VERSION 5.7 ;
BUSBITCHARS "[]" ;
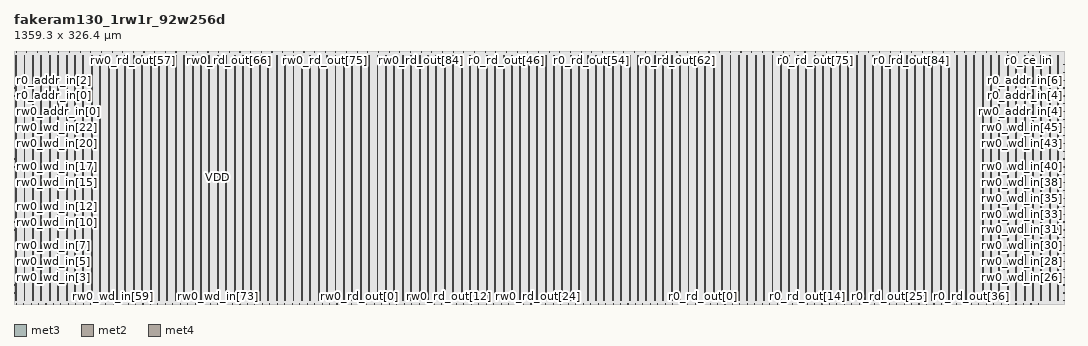
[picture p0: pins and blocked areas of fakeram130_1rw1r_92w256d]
MACRO fakeram130_1rw1r_92w256d
  FOREIGN fakeram130_1rw1r_92w256d 0 0 ;
  SYMMETRY X Y R90 ;
  SIZE 1359.300 BY 326.400 ;
  CLASS BLOCK ;
  PIN rw0_wd_in[0]
    DIRECTION INPUT ;
    USE SIGNAL ;
    SHAPE ABUTMENT ;
    PORT
      LAYER met3 ;
      RECT 0.000 3.930 0.900 4.230 ;
    END
  END rw0_wd_in[0]
  PIN rw0_wd_in[1]
    DIRECTION INPUT ;
    USE SIGNAL ;
    SHAPE ABUTMENT ;
    PORT
      LAYER met3 ;
      RECT 0.000 14.130 0.900 14.430 ;
    END
  END rw0_wd_in[1]
  PIN rw0_wd_in[2]
    DIRECTION INPUT ;
    USE SIGNAL ;
    SHAPE ABUTMENT ;
    PORT
      LAYER met3 ;
      RECT 0.000 24.330 0.900 24.630 ;
    END
  END rw0_wd_in[2]
  PIN rw0_wd_in[3]
    DIRECTION INPUT ;
    USE SIGNAL ;
    SHAPE ABUTMENT ;
    PORT
      LAYER met3 ;
      RECT 0.000 34.530 0.900 34.830 ;
    END
  END rw0_wd_in[3]
  PIN rw0_wd_in[4]
    DIRECTION INPUT ;
    USE SIGNAL ;
    SHAPE ABUTMENT ;
    PORT
      LAYER met3 ;
      RECT 0.000 44.730 0.900 45.030 ;
    END
  END rw0_wd_in[4]
  PIN rw0_wd_in[5]
    DIRECTION INPUT ;
    USE SIGNAL ;
    SHAPE ABUTMENT ;
    PORT
      LAYER met3 ;
      RECT 0.000 54.930 0.900 55.230 ;
    END
  END rw0_wd_in[5]
  PIN rw0_wd_in[6]
    DIRECTION INPUT ;
    USE SIGNAL ;
    SHAPE ABUTMENT ;
    PORT
      LAYER met3 ;
      RECT 0.000 65.130 0.900 65.430 ;
    END
  END rw0_wd_in[6]
  PIN rw0_wd_in[7]
    DIRECTION INPUT ;
    USE SIGNAL ;
    SHAPE ABUTMENT ;
    PORT
      LAYER met3 ;
      RECT 0.000 75.330 0.900 75.630 ;
    END
  END rw0_wd_in[7]
  PIN rw0_wd_in[8]
    DIRECTION INPUT ;
    USE SIGNAL ;
    SHAPE ABUTMENT ;
    PORT
      LAYER met3 ;
      RECT 0.000 85.530 0.900 85.830 ;
    END
  END rw0_wd_in[8]
  PIN rw0_wd_in[9]
    DIRECTION INPUT ;
    USE SIGNAL ;
    SHAPE ABUTMENT ;
    PORT
      LAYER met3 ;
      RECT 0.000 95.730 0.900 96.030 ;
    END
  END rw0_wd_in[9]
  PIN rw0_wd_in[10]
    DIRECTION INPUT ;
    USE SIGNAL ;
    SHAPE ABUTMENT ;
    PORT
      LAYER met3 ;
      RECT 0.000 105.930 0.900 106.230 ;
    END
  END rw0_wd_in[10]
  PIN rw0_wd_in[11]
    DIRECTION INPUT ;
    USE SIGNAL ;
    SHAPE ABUTMENT ;
    PORT
      LAYER met3 ;
      RECT 0.000 116.130 0.900 116.430 ;
    END
  END rw0_wd_in[11]
  PIN rw0_wd_in[12]
    DIRECTION INPUT ;
    USE SIGNAL ;
    SHAPE ABUTMENT ;
    PORT
      LAYER met3 ;
      RECT 0.000 126.330 0.900 126.630 ;
    END
  END rw0_wd_in[12]
  PIN rw0_wd_in[13]
    DIRECTION INPUT ;
    USE SIGNAL ;
    SHAPE ABUTMENT ;
    PORT
      LAYER met3 ;
      RECT 0.000 136.530 0.900 136.830 ;
    END
  END rw0_wd_in[13]
  PIN rw0_wd_in[14]
    DIRECTION INPUT ;
    USE SIGNAL ;
    SHAPE ABUTMENT ;
    PORT
      LAYER met3 ;
      RECT 0.000 146.730 0.900 147.030 ;
    END
  END rw0_wd_in[14]
  PIN rw0_wd_in[15]
    DIRECTION INPUT ;
    USE SIGNAL ;
    SHAPE ABUTMENT ;
    PORT
      LAYER met3 ;
      RECT 0.000 156.930 0.900 157.230 ;
    END
  END rw0_wd_in[15]
  PIN rw0_wd_in[16]
    DIRECTION INPUT ;
    USE SIGNAL ;
    SHAPE ABUTMENT ;
    PORT
      LAYER met3 ;
      RECT 0.000 167.130 0.900 167.430 ;
    END
  END rw0_wd_in[16]
  PIN rw0_wd_in[17]
    DIRECTION INPUT ;
    USE SIGNAL ;
    SHAPE ABUTMENT ;
    PORT
      LAYER met3 ;
      RECT 0.000 177.330 0.900 177.630 ;
    END
  END rw0_wd_in[17]
  PIN rw0_wd_in[18]
    DIRECTION INPUT ;
    USE SIGNAL ;
    SHAPE ABUTMENT ;
    PORT
      LAYER met3 ;
      RECT 0.000 187.530 0.900 187.830 ;
    END
  END rw0_wd_in[18]
  PIN rw0_wd_in[19]
    DIRECTION INPUT ;
    USE SIGNAL ;
    SHAPE ABUTMENT ;
    PORT
      LAYER met3 ;
      RECT 0.000 197.730 0.900 198.030 ;
    END
  END rw0_wd_in[19]
  PIN rw0_wd_in[20]
    DIRECTION INPUT ;
    USE SIGNAL ;
    SHAPE ABUTMENT ;
    PORT
      LAYER met3 ;
      RECT 0.000 207.930 0.900 208.230 ;
    END
  END rw0_wd_in[20]
  PIN rw0_wd_in[21]
    DIRECTION INPUT ;
    USE SIGNAL ;
    SHAPE ABUTMENT ;
    PORT
      LAYER met3 ;
      RECT 0.000 218.130 0.900 218.430 ;
    END
  END rw0_wd_in[21]
  PIN rw0_wd_in[22]
    DIRECTION INPUT ;
    USE SIGNAL ;
    SHAPE ABUTMENT ;
    PORT
      LAYER met3 ;
      RECT 0.000 228.330 0.900 228.630 ;
    END
  END rw0_wd_in[22]
  PIN rw0_wd_in[23]
    DIRECTION INPUT ;
    USE SIGNAL ;
    SHAPE ABUTMENT ;
    PORT
      LAYER met3 ;
      RECT 1358.400 3.930 1359.300 4.230 ;
    END
  END rw0_wd_in[23]
  PIN rw0_wd_in[24]
    DIRECTION INPUT ;
    USE SIGNAL ;
    SHAPE ABUTMENT ;
    PORT
      LAYER met3 ;
      RECT 1358.400 14.130 1359.300 14.430 ;
    END
  END rw0_wd_in[24]
  PIN rw0_wd_in[25]
    DIRECTION INPUT ;
    USE SIGNAL ;
    SHAPE ABUTMENT ;
    PORT
      LAYER met3 ;
      RECT 1358.400 24.330 1359.300 24.630 ;
    END
  END rw0_wd_in[25]
  PIN rw0_wd_in[26]
    DIRECTION INPUT ;
    USE SIGNAL ;
    SHAPE ABUTMENT ;
    PORT
      LAYER met3 ;
      RECT 1358.400 34.530 1359.300 34.830 ;
    END
  END rw0_wd_in[26]
  PIN rw0_wd_in[27]
    DIRECTION INPUT ;
    USE SIGNAL ;
    SHAPE ABUTMENT ;
    PORT
      LAYER met3 ;
      RECT 1358.400 44.730 1359.300 45.030 ;
    END
  END rw0_wd_in[27]
  PIN rw0_wd_in[28]
    DIRECTION INPUT ;
    USE SIGNAL ;
    SHAPE ABUTMENT ;
    PORT
      LAYER met3 ;
      RECT 1358.400 54.930 1359.300 55.230 ;
    END
  END rw0_wd_in[28]
  PIN rw0_wd_in[29]
    DIRECTION INPUT ;
    USE SIGNAL ;
    SHAPE ABUTMENT ;
    PORT
      LAYER met3 ;
      RECT 1358.400 65.130 1359.300 65.430 ;
    END
  END rw0_wd_in[29]
  PIN rw0_wd_in[30]
    DIRECTION INPUT ;
    USE SIGNAL ;
    SHAPE ABUTMENT ;
    PORT
      LAYER met3 ;
      RECT 1358.400 75.330 1359.300 75.630 ;
    END
  END rw0_wd_in[30]
  PIN rw0_wd_in[31]
    DIRECTION INPUT ;
    USE SIGNAL ;
    SHAPE ABUTMENT ;
    PORT
      LAYER met3 ;
      RECT 1358.400 85.530 1359.300 85.830 ;
    END
  END rw0_wd_in[31]
  PIN rw0_wd_in[32]
    DIRECTION INPUT ;
    USE SIGNAL ;
    SHAPE ABUTMENT ;
    PORT
      LAYER met3 ;
      RECT 1358.400 95.730 1359.300 96.030 ;
    END
  END rw0_wd_in[32]
  PIN rw0_wd_in[33]
    DIRECTION INPUT ;
    USE SIGNAL ;
    SHAPE ABUTMENT ;
    PORT
      LAYER met3 ;
      RECT 1358.400 105.930 1359.300 106.230 ;
    END
  END rw0_wd_in[33]
  PIN rw0_wd_in[34]
    DIRECTION INPUT ;
    USE SIGNAL ;
    SHAPE ABUTMENT ;
    PORT
      LAYER met3 ;
      RECT 1358.400 116.130 1359.300 116.430 ;
    END
  END rw0_wd_in[34]
  PIN rw0_wd_in[35]
    DIRECTION INPUT ;
    USE SIGNAL ;
    SHAPE ABUTMENT ;
    PORT
      LAYER met3 ;
      RECT 1358.400 126.330 1359.300 126.630 ;
    END
  END rw0_wd_in[35]
  PIN rw0_wd_in[36]
    DIRECTION INPUT ;
    USE SIGNAL ;
    SHAPE ABUTMENT ;
    PORT
      LAYER met3 ;
      RECT 1358.400 136.530 1359.300 136.830 ;
    END
  END rw0_wd_in[36]
  PIN rw0_wd_in[37]
    DIRECTION INPUT ;
    USE SIGNAL ;
    SHAPE ABUTMENT ;
    PORT
      LAYER met3 ;
      RECT 1358.400 146.730 1359.300 147.030 ;
    END
  END rw0_wd_in[37]
  PIN rw0_wd_in[38]
    DIRECTION INPUT ;
    USE SIGNAL ;
    SHAPE ABUTMENT ;
    PORT
      LAYER met3 ;
      RECT 1358.400 156.930 1359.300 157.230 ;
    END
  END rw0_wd_in[38]
  PIN rw0_wd_in[39]
    DIRECTION INPUT ;
    USE SIGNAL ;
    SHAPE ABUTMENT ;
    PORT
      LAYER met3 ;
      RECT 1358.400 167.130 1359.300 167.430 ;
    END
  END rw0_wd_in[39]
  PIN rw0_wd_in[40]
    DIRECTION INPUT ;
    USE SIGNAL ;
    SHAPE ABUTMENT ;
    PORT
      LAYER met3 ;
      RECT 1358.400 177.330 1359.300 177.630 ;
    END
  END rw0_wd_in[40]
  PIN rw0_wd_in[41]
    DIRECTION INPUT ;
    USE SIGNAL ;
    SHAPE ABUTMENT ;
    PORT
      LAYER met3 ;
      RECT 1358.400 187.530 1359.300 187.830 ;
    END
  END rw0_wd_in[41]
  PIN rw0_wd_in[42]
    DIRECTION INPUT ;
    USE SIGNAL ;
    SHAPE ABUTMENT ;
    PORT
      LAYER met3 ;
      RECT 1358.400 197.730 1359.300 198.030 ;
    END
  END rw0_wd_in[42]
  PIN rw0_wd_in[43]
    DIRECTION INPUT ;
    USE SIGNAL ;
    SHAPE ABUTMENT ;
    PORT
      LAYER met3 ;
      RECT 1358.400 207.930 1359.300 208.230 ;
    END
  END rw0_wd_in[43]
  PIN rw0_wd_in[44]
    DIRECTION INPUT ;
    USE SIGNAL ;
    SHAPE ABUTMENT ;
    PORT
      LAYER met3 ;
      RECT 1358.400 218.130 1359.300 218.430 ;
    END
  END rw0_wd_in[44]
  PIN rw0_wd_in[45]
    DIRECTION INPUT ;
    USE SIGNAL ;
    SHAPE ABUTMENT ;
    PORT
      LAYER met3 ;
      RECT 1358.400 228.330 1359.300 228.630 ;
    END
  END rw0_wd_in[45]
  PIN rw0_wd_in[46]
    DIRECTION OUTPUT ;
    USE SIGNAL ;
    SHAPE ABUTMENT ;
    PORT
      LAYER met2 ;
      RECT 2.690 0.000 2.830 0.420 ;
    END
  END rw0_wd_in[46]
  PIN rw0_wd_in[47]
    DIRECTION OUTPUT ;
    USE SIGNAL ;
    SHAPE ABUTMENT ;
    PORT
      LAYER met2 ;
      RECT 12.350 0.000 12.490 0.420 ;
    END
  END rw0_wd_in[47]
  PIN rw0_wd_in[48]
    DIRECTION OUTPUT ;
    USE SIGNAL ;
    SHAPE ABUTMENT ;
    PORT
      LAYER met2 ;
      RECT 22.010 0.000 22.150 0.420 ;
    END
  END rw0_wd_in[48]
  PIN rw0_wd_in[49]
    DIRECTION OUTPUT ;
    USE SIGNAL ;
    SHAPE ABUTMENT ;
    PORT
      LAYER met2 ;
      RECT 31.670 0.000 31.810 0.420 ;
    END
  END rw0_wd_in[49]
  PIN rw0_wd_in[50]
    DIRECTION OUTPUT ;
    USE SIGNAL ;
    SHAPE ABUTMENT ;
    PORT
      LAYER met2 ;
      RECT 41.330 0.000 41.470 0.420 ;
    END
  END rw0_wd_in[50]
  PIN rw0_wd_in[51]
    DIRECTION OUTPUT ;
    USE SIGNAL ;
    SHAPE ABUTMENT ;
    PORT
      LAYER met2 ;
      RECT 50.990 0.000 51.130 0.420 ;
    END
  END rw0_wd_in[51]
  PIN rw0_wd_in[52]
    DIRECTION OUTPUT ;
    USE SIGNAL ;
    SHAPE ABUTMENT ;
    PORT
      LAYER met2 ;
      RECT 60.650 0.000 60.790 0.420 ;
    END
  END rw0_wd_in[52]
  PIN rw0_wd_in[53]
    DIRECTION OUTPUT ;
    USE SIGNAL ;
    SHAPE ABUTMENT ;
    PORT
      LAYER met2 ;
      RECT 70.310 0.000 70.450 0.420 ;
    END
  END rw0_wd_in[53]
  PIN rw0_wd_in[54]
    DIRECTION OUTPUT ;
    USE SIGNAL ;
    SHAPE ABUTMENT ;
    PORT
      LAYER met2 ;
      RECT 79.970 0.000 80.110 0.420 ;
    END
  END rw0_wd_in[54]
  PIN rw0_wd_in[55]
    DIRECTION OUTPUT ;
    USE SIGNAL ;
    SHAPE ABUTMENT ;
    PORT
      LAYER met2 ;
      RECT 89.630 0.000 89.770 0.420 ;
    END
  END rw0_wd_in[55]
  PIN rw0_wd_in[56]
    DIRECTION OUTPUT ;
    USE SIGNAL ;
    SHAPE ABUTMENT ;
    PORT
      LAYER met2 ;
      RECT 99.290 0.000 99.430 0.420 ;
    END
  END rw0_wd_in[56]
  PIN rw0_wd_in[57]
    DIRECTION OUTPUT ;
    USE SIGNAL ;
    SHAPE ABUTMENT ;
    PORT
      LAYER met2 ;
      RECT 108.950 0.000 109.090 0.420 ;
    END
  END rw0_wd_in[57]
  PIN rw0_wd_in[58]
    DIRECTION OUTPUT ;
    USE SIGNAL ;
    SHAPE ABUTMENT ;
    PORT
      LAYER met2 ;
      RECT 118.610 0.000 118.750 0.420 ;
    END
  END rw0_wd_in[58]
  PIN rw0_wd_in[59]
    DIRECTION OUTPUT ;
    USE SIGNAL ;
    SHAPE ABUTMENT ;
    PORT
      LAYER met2 ;
      RECT 128.270 0.000 128.410 0.420 ;
    END
  END rw0_wd_in[59]
  PIN rw0_wd_in[60]
    DIRECTION OUTPUT ;
    USE SIGNAL ;
    SHAPE ABUTMENT ;
    PORT
      LAYER met2 ;
      RECT 137.930 0.000 138.070 0.420 ;
    END
  END rw0_wd_in[60]
  PIN rw0_wd_in[61]
    DIRECTION OUTPUT ;
    USE SIGNAL ;
    SHAPE ABUTMENT ;
    PORT
      LAYER met2 ;
      RECT 147.590 0.000 147.730 0.420 ;
    END
  END rw0_wd_in[61]
  PIN rw0_wd_in[62]
    DIRECTION OUTPUT ;
    USE SIGNAL ;
    SHAPE ABUTMENT ;
    PORT
      LAYER met2 ;
      RECT 157.250 0.000 157.390 0.420 ;
    END
  END rw0_wd_in[62]
  PIN rw0_wd_in[63]
    DIRECTION OUTPUT ;
    USE SIGNAL ;
    SHAPE ABUTMENT ;
    PORT
      LAYER met2 ;
      RECT 166.910 0.000 167.050 0.420 ;
    END
  END rw0_wd_in[63]
  PIN rw0_wd_in[64]
    DIRECTION OUTPUT ;
    USE SIGNAL ;
    SHAPE ABUTMENT ;
    PORT
      LAYER met2 ;
      RECT 176.570 0.000 176.710 0.420 ;
    END
  END rw0_wd_in[64]
  PIN rw0_wd_in[65]
    DIRECTION OUTPUT ;
    USE SIGNAL ;
    SHAPE ABUTMENT ;
    PORT
      LAYER met2 ;
      RECT 186.230 0.000 186.370 0.420 ;
    END
  END rw0_wd_in[65]
  PIN rw0_wd_in[66]
    DIRECTION OUTPUT ;
    USE SIGNAL ;
    SHAPE ABUTMENT ;
    PORT
      LAYER met2 ;
      RECT 195.890 0.000 196.030 0.420 ;
    END
  END rw0_wd_in[66]
  PIN rw0_wd_in[67]
    DIRECTION OUTPUT ;
    USE SIGNAL ;
    SHAPE ABUTMENT ;
    PORT
      LAYER met2 ;
      RECT 205.550 0.000 205.690 0.420 ;
    END
  END rw0_wd_in[67]
  PIN rw0_wd_in[68]
    DIRECTION OUTPUT ;
    USE SIGNAL ;
    SHAPE ABUTMENT ;
    PORT
      LAYER met2 ;
      RECT 215.210 0.000 215.350 0.420 ;
    END
  END rw0_wd_in[68]
  PIN rw0_wd_in[69]
    DIRECTION OUTPUT ;
    USE SIGNAL ;
    SHAPE ABUTMENT ;
    PORT
      LAYER met2 ;
      RECT 224.870 0.000 225.010 0.420 ;
    END
  END rw0_wd_in[69]
  PIN rw0_wd_in[70]
    DIRECTION OUTPUT ;
    USE SIGNAL ;
    SHAPE ABUTMENT ;
    PORT
      LAYER met2 ;
      RECT 234.530 0.000 234.670 0.420 ;
    END
  END rw0_wd_in[70]
  PIN rw0_wd_in[71]
    DIRECTION OUTPUT ;
    USE SIGNAL ;
    SHAPE ABUTMENT ;
    PORT
      LAYER met2 ;
      RECT 244.190 0.000 244.330 0.420 ;
    END
  END rw0_wd_in[71]
  PIN rw0_wd_in[72]
    DIRECTION OUTPUT ;
    USE SIGNAL ;
    SHAPE ABUTMENT ;
    PORT
      LAYER met2 ;
      RECT 253.850 0.000 253.990 0.420 ;
    END
  END rw0_wd_in[72]
  PIN rw0_wd_in[73]
    DIRECTION OUTPUT ;
    USE SIGNAL ;
    SHAPE ABUTMENT ;
    PORT
      LAYER met2 ;
      RECT 263.510 0.000 263.650 0.420 ;
    END
  END rw0_wd_in[73]
  PIN rw0_wd_in[74]
    DIRECTION OUTPUT ;
    USE SIGNAL ;
    SHAPE ABUTMENT ;
    PORT
      LAYER met2 ;
      RECT 273.170 0.000 273.310 0.420 ;
    END
  END rw0_wd_in[74]
  PIN rw0_wd_in[75]
    DIRECTION OUTPUT ;
    USE SIGNAL ;
    SHAPE ABUTMENT ;
    PORT
      LAYER met2 ;
      RECT 282.830 0.000 282.970 0.420 ;
    END
  END rw0_wd_in[75]
  PIN rw0_wd_in[76]
    DIRECTION OUTPUT ;
    USE SIGNAL ;
    SHAPE ABUTMENT ;
    PORT
      LAYER met2 ;
      RECT 292.490 0.000 292.630 0.420 ;
    END
  END rw0_wd_in[76]
  PIN rw0_wd_in[77]
    DIRECTION OUTPUT ;
    USE SIGNAL ;
    SHAPE ABUTMENT ;
    PORT
      LAYER met2 ;
      RECT 302.150 0.000 302.290 0.420 ;
    END
  END rw0_wd_in[77]
  PIN rw0_wd_in[78]
    DIRECTION OUTPUT ;
    USE SIGNAL ;
    SHAPE ABUTMENT ;
    PORT
      LAYER met2 ;
      RECT 311.810 0.000 311.950 0.420 ;
    END
  END rw0_wd_in[78]
  PIN rw0_wd_in[79]
    DIRECTION OUTPUT ;
    USE SIGNAL ;
    SHAPE ABUTMENT ;
    PORT
      LAYER met2 ;
      RECT 321.470 0.000 321.610 0.420 ;
    END
  END rw0_wd_in[79]
  PIN rw0_wd_in[80]
    DIRECTION OUTPUT ;
    USE SIGNAL ;
    SHAPE ABUTMENT ;
    PORT
      LAYER met2 ;
      RECT 331.130 0.000 331.270 0.420 ;
    END
  END rw0_wd_in[80]
  PIN rw0_wd_in[81]
    DIRECTION OUTPUT ;
    USE SIGNAL ;
    SHAPE ABUTMENT ;
    PORT
      LAYER met2 ;
      RECT 340.790 0.000 340.930 0.420 ;
    END
  END rw0_wd_in[81]
  PIN rw0_wd_in[82]
    DIRECTION OUTPUT ;
    USE SIGNAL ;
    SHAPE ABUTMENT ;
    PORT
      LAYER met2 ;
      RECT 350.450 0.000 350.590 0.420 ;
    END
  END rw0_wd_in[82]
  PIN rw0_wd_in[83]
    DIRECTION OUTPUT ;
    USE SIGNAL ;
    SHAPE ABUTMENT ;
    PORT
      LAYER met2 ;
      RECT 360.110 0.000 360.250 0.420 ;
    END
  END rw0_wd_in[83]
  PIN rw0_wd_in[84]
    DIRECTION OUTPUT ;
    USE SIGNAL ;
    SHAPE ABUTMENT ;
    PORT
      LAYER met2 ;
      RECT 369.770 0.000 369.910 0.420 ;
    END
  END rw0_wd_in[84]
  PIN rw0_wd_in[85]
    DIRECTION OUTPUT ;
    USE SIGNAL ;
    SHAPE ABUTMENT ;
    PORT
      LAYER met2 ;
      RECT 379.430 0.000 379.570 0.420 ;
    END
  END rw0_wd_in[85]
  PIN rw0_wd_in[86]
    DIRECTION OUTPUT ;
    USE SIGNAL ;
    SHAPE ABUTMENT ;
    PORT
      LAYER met2 ;
      RECT 389.090 0.000 389.230 0.420 ;
    END
  END rw0_wd_in[86]
  PIN rw0_wd_in[87]
    DIRECTION OUTPUT ;
    USE SIGNAL ;
    SHAPE ABUTMENT ;
    PORT
      LAYER met2 ;
      RECT 398.750 0.000 398.890 0.420 ;
    END
  END rw0_wd_in[87]
  PIN rw0_wd_in[88]
    DIRECTION OUTPUT ;
    USE SIGNAL ;
    SHAPE ABUTMENT ;
    PORT
      LAYER met2 ;
      RECT 408.410 0.000 408.550 0.420 ;
    END
  END rw0_wd_in[88]
  PIN rw0_wd_in[89]
    DIRECTION OUTPUT ;
    USE SIGNAL ;
    SHAPE ABUTMENT ;
    PORT
      LAYER met2 ;
      RECT 418.070 0.000 418.210 0.420 ;
    END
  END rw0_wd_in[89]
  PIN rw0_wd_in[90]
    DIRECTION OUTPUT ;
    USE SIGNAL ;
    SHAPE ABUTMENT ;
    PORT
      LAYER met2 ;
      RECT 427.730 0.000 427.870 0.420 ;
    END
  END rw0_wd_in[90]
  PIN rw0_wd_in[91]
    DIRECTION OUTPUT ;
    USE SIGNAL ;
    SHAPE ABUTMENT ;
    PORT
      LAYER met2 ;
      RECT 437.390 0.000 437.530 0.420 ;
    END
  END rw0_wd_in[91]
  PIN rw0_rd_out[0]
    DIRECTION OUTPUT ;
    USE SIGNAL ;
    SHAPE ABUTMENT ;
    PORT
      LAYER met2 ;
      RECT 447.050 0.000 447.190 0.420 ;
    END
  END rw0_rd_out[0]
  PIN rw0_rd_out[1]
    DIRECTION OUTPUT ;
    USE SIGNAL ;
    SHAPE ABUTMENT ;
    PORT
      LAYER met2 ;
      RECT 456.710 0.000 456.850 0.420 ;
    END
  END rw0_rd_out[1]
  PIN rw0_rd_out[2]
    DIRECTION OUTPUT ;
    USE SIGNAL ;
    SHAPE ABUTMENT ;
    PORT
      LAYER met2 ;
      RECT 466.370 0.000 466.510 0.420 ;
    END
  END rw0_rd_out[2]
  PIN rw0_rd_out[3]
    DIRECTION OUTPUT ;
    USE SIGNAL ;
    SHAPE ABUTMENT ;
    PORT
      LAYER met2 ;
      RECT 476.030 0.000 476.170 0.420 ;
    END
  END rw0_rd_out[3]
  PIN rw0_rd_out[4]
    DIRECTION OUTPUT ;
    USE SIGNAL ;
    SHAPE ABUTMENT ;
    PORT
      LAYER met2 ;
      RECT 485.690 0.000 485.830 0.420 ;
    END
  END rw0_rd_out[4]
  PIN rw0_rd_out[5]
    DIRECTION OUTPUT ;
    USE SIGNAL ;
    SHAPE ABUTMENT ;
    PORT
      LAYER met2 ;
      RECT 495.350 0.000 495.490 0.420 ;
    END
  END rw0_rd_out[5]
  PIN rw0_rd_out[6]
    DIRECTION OUTPUT ;
    USE SIGNAL ;
    SHAPE ABUTMENT ;
    PORT
      LAYER met2 ;
      RECT 505.010 0.000 505.150 0.420 ;
    END
  END rw0_rd_out[6]
  PIN rw0_rd_out[7]
    DIRECTION OUTPUT ;
    USE SIGNAL ;
    SHAPE ABUTMENT ;
    PORT
      LAYER met2 ;
      RECT 514.670 0.000 514.810 0.420 ;
    END
  END rw0_rd_out[7]
  PIN rw0_rd_out[8]
    DIRECTION OUTPUT ;
    USE SIGNAL ;
    SHAPE ABUTMENT ;
    PORT
      LAYER met2 ;
      RECT 524.330 0.000 524.470 0.420 ;
    END
  END rw0_rd_out[8]
  PIN rw0_rd_out[9]
    DIRECTION OUTPUT ;
    USE SIGNAL ;
    SHAPE ABUTMENT ;
    PORT
      LAYER met2 ;
      RECT 533.990 0.000 534.130 0.420 ;
    END
  END rw0_rd_out[9]
  PIN rw0_rd_out[10]
    DIRECTION OUTPUT ;
    USE SIGNAL ;
    SHAPE ABUTMENT ;
    PORT
      LAYER met2 ;
      RECT 543.650 0.000 543.790 0.420 ;
    END
  END rw0_rd_out[10]
  PIN rw0_rd_out[11]
    DIRECTION OUTPUT ;
    USE SIGNAL ;
    SHAPE ABUTMENT ;
    PORT
      LAYER met2 ;
      RECT 553.310 0.000 553.450 0.420 ;
    END
  END rw0_rd_out[11]
  PIN rw0_rd_out[12]
    DIRECTION OUTPUT ;
    USE SIGNAL ;
    SHAPE ABUTMENT ;
    PORT
      LAYER met2 ;
      RECT 562.970 0.000 563.110 0.420 ;
    END
  END rw0_rd_out[12]
  PIN rw0_rd_out[13]
    DIRECTION OUTPUT ;
    USE SIGNAL ;
    SHAPE ABUTMENT ;
    PORT
      LAYER met2 ;
      RECT 572.630 0.000 572.770 0.420 ;
    END
  END rw0_rd_out[13]
  PIN rw0_rd_out[14]
    DIRECTION OUTPUT ;
    USE SIGNAL ;
    SHAPE ABUTMENT ;
    PORT
      LAYER met2 ;
      RECT 582.290 0.000 582.430 0.420 ;
    END
  END rw0_rd_out[14]
  PIN rw0_rd_out[15]
    DIRECTION OUTPUT ;
    USE SIGNAL ;
    SHAPE ABUTMENT ;
    PORT
      LAYER met2 ;
      RECT 591.950 0.000 592.090 0.420 ;
    END
  END rw0_rd_out[15]
  PIN rw0_rd_out[16]
    DIRECTION OUTPUT ;
    USE SIGNAL ;
    SHAPE ABUTMENT ;
    PORT
      LAYER met2 ;
      RECT 601.610 0.000 601.750 0.420 ;
    END
  END rw0_rd_out[16]
  PIN rw0_rd_out[17]
    DIRECTION OUTPUT ;
    USE SIGNAL ;
    SHAPE ABUTMENT ;
    PORT
      LAYER met2 ;
      RECT 611.270 0.000 611.410 0.420 ;
    END
  END rw0_rd_out[17]
  PIN rw0_rd_out[18]
    DIRECTION OUTPUT ;
    USE SIGNAL ;
    SHAPE ABUTMENT ;
    PORT
      LAYER met2 ;
      RECT 620.930 0.000 621.070 0.420 ;
    END
  END rw0_rd_out[18]
  PIN rw0_rd_out[19]
    DIRECTION OUTPUT ;
    USE SIGNAL ;
    SHAPE ABUTMENT ;
    PORT
      LAYER met2 ;
      RECT 630.590 0.000 630.730 0.420 ;
    END
  END rw0_rd_out[19]
  PIN rw0_rd_out[20]
    DIRECTION OUTPUT ;
    USE SIGNAL ;
    SHAPE ABUTMENT ;
    PORT
      LAYER met2 ;
      RECT 640.250 0.000 640.390 0.420 ;
    END
  END rw0_rd_out[20]
  PIN rw0_rd_out[21]
    DIRECTION OUTPUT ;
    USE SIGNAL ;
    SHAPE ABUTMENT ;
    PORT
      LAYER met2 ;
      RECT 649.910 0.000 650.050 0.420 ;
    END
  END rw0_rd_out[21]
  PIN rw0_rd_out[22]
    DIRECTION OUTPUT ;
    USE SIGNAL ;
    SHAPE ABUTMENT ;
    PORT
      LAYER met2 ;
      RECT 659.570 0.000 659.710 0.420 ;
    END
  END rw0_rd_out[22]
  PIN rw0_rd_out[23]
    DIRECTION OUTPUT ;
    USE SIGNAL ;
    SHAPE ABUTMENT ;
    PORT
      LAYER met2 ;
      RECT 669.230 0.000 669.370 0.420 ;
    END
  END rw0_rd_out[23]
  PIN rw0_rd_out[24]
    DIRECTION OUTPUT ;
    USE SIGNAL ;
    SHAPE ABUTMENT ;
    PORT
      LAYER met2 ;
      RECT 678.890 0.000 679.030 0.420 ;
    END
  END rw0_rd_out[24]
  PIN rw0_rd_out[25]
    DIRECTION OUTPUT ;
    USE SIGNAL ;
    SHAPE ABUTMENT ;
    PORT
      LAYER met2 ;
      RECT 688.550 0.000 688.690 0.420 ;
    END
  END rw0_rd_out[25]
  PIN rw0_rd_out[26]
    DIRECTION OUTPUT ;
    USE SIGNAL ;
    SHAPE ABUTMENT ;
    PORT
      LAYER met2 ;
      RECT 698.210 0.000 698.350 0.420 ;
    END
  END rw0_rd_out[26]
  PIN rw0_rd_out[27]
    DIRECTION OUTPUT ;
    USE SIGNAL ;
    SHAPE ABUTMENT ;
    PORT
      LAYER met2 ;
      RECT 707.870 0.000 708.010 0.420 ;
    END
  END rw0_rd_out[27]
  PIN rw0_rd_out[28]
    DIRECTION OUTPUT ;
    USE SIGNAL ;
    SHAPE ABUTMENT ;
    PORT
      LAYER met2 ;
      RECT 717.530 0.000 717.670 0.420 ;
    END
  END rw0_rd_out[28]
  PIN rw0_rd_out[29]
    DIRECTION OUTPUT ;
    USE SIGNAL ;
    SHAPE ABUTMENT ;
    PORT
      LAYER met2 ;
      RECT 727.190 0.000 727.330 0.420 ;
    END
  END rw0_rd_out[29]
  PIN rw0_rd_out[30]
    DIRECTION OUTPUT ;
    USE SIGNAL ;
    SHAPE ABUTMENT ;
    PORT
      LAYER met2 ;
      RECT 736.850 0.000 736.990 0.420 ;
    END
  END rw0_rd_out[30]
  PIN rw0_rd_out[31]
    DIRECTION OUTPUT ;
    USE SIGNAL ;
    SHAPE ABUTMENT ;
    PORT
      LAYER met2 ;
      RECT 746.510 0.000 746.650 0.420 ;
    END
  END rw0_rd_out[31]
  PIN rw0_rd_out[32]
    DIRECTION OUTPUT ;
    USE SIGNAL ;
    SHAPE ABUTMENT ;
    PORT
      LAYER met2 ;
      RECT 756.170 0.000 756.310 0.420 ;
    END
  END rw0_rd_out[32]
  PIN rw0_rd_out[33]
    DIRECTION OUTPUT ;
    USE SIGNAL ;
    SHAPE ABUTMENT ;
    PORT
      LAYER met2 ;
      RECT 765.830 0.000 765.970 0.420 ;
    END
  END rw0_rd_out[33]
  PIN rw0_rd_out[34]
    DIRECTION OUTPUT ;
    USE SIGNAL ;
    SHAPE ABUTMENT ;
    PORT
      LAYER met2 ;
      RECT 775.490 0.000 775.630 0.420 ;
    END
  END rw0_rd_out[34]
  PIN rw0_rd_out[35]
    DIRECTION OUTPUT ;
    USE SIGNAL ;
    SHAPE ABUTMENT ;
    PORT
      LAYER met2 ;
      RECT 785.150 0.000 785.290 0.420 ;
    END
  END rw0_rd_out[35]
  PIN rw0_rd_out[36]
    DIRECTION OUTPUT ;
    USE SIGNAL ;
    SHAPE ABUTMENT ;
    PORT
      LAYER met2 ;
      RECT 794.810 0.000 794.950 0.420 ;
    END
  END rw0_rd_out[36]
  PIN rw0_rd_out[37]
    DIRECTION OUTPUT ;
    USE SIGNAL ;
    SHAPE ABUTMENT ;
    PORT
      LAYER met2 ;
      RECT 804.470 0.000 804.610 0.420 ;
    END
  END rw0_rd_out[37]
  PIN rw0_rd_out[38]
    DIRECTION OUTPUT ;
    USE SIGNAL ;
    SHAPE ABUTMENT ;
    PORT
      LAYER met2 ;
      RECT 814.130 0.000 814.270 0.420 ;
    END
  END rw0_rd_out[38]
  PIN rw0_rd_out[39]
    DIRECTION OUTPUT ;
    USE SIGNAL ;
    SHAPE ABUTMENT ;
    PORT
      LAYER met2 ;
      RECT 823.790 0.000 823.930 0.420 ;
    END
  END rw0_rd_out[39]
  PIN rw0_rd_out[40]
    DIRECTION OUTPUT ;
    USE SIGNAL ;
    SHAPE ABUTMENT ;
    PORT
      LAYER met2 ;
      RECT 833.450 0.000 833.590 0.420 ;
    END
  END rw0_rd_out[40]
  PIN rw0_rd_out[41]
    DIRECTION OUTPUT ;
    USE SIGNAL ;
    SHAPE ABUTMENT ;
    PORT
      LAYER met2 ;
      RECT 843.110 0.000 843.250 0.420 ;
    END
  END rw0_rd_out[41]
  PIN rw0_rd_out[42]
    DIRECTION OUTPUT ;
    USE SIGNAL ;
    SHAPE ABUTMENT ;
    PORT
      LAYER met2 ;
      RECT 852.770 0.000 852.910 0.420 ;
    END
  END rw0_rd_out[42]
  PIN rw0_rd_out[43]
    DIRECTION OUTPUT ;
    USE SIGNAL ;
    SHAPE ABUTMENT ;
    PORT
      LAYER met2 ;
      RECT 862.430 0.000 862.570 0.420 ;
    END
  END rw0_rd_out[43]
  PIN rw0_rd_out[44]
    DIRECTION OUTPUT ;
    USE SIGNAL ;
    SHAPE ABUTMENT ;
    PORT
      LAYER met2 ;
      RECT 872.090 0.000 872.230 0.420 ;
    END
  END rw0_rd_out[44]
  PIN rw0_rd_out[45]
    DIRECTION OUTPUT ;
    USE SIGNAL ;
    SHAPE ABUTMENT ;
    PORT
      LAYER met2 ;
      RECT 881.750 0.000 881.890 0.420 ;
    END
  END rw0_rd_out[45]
  PIN rw0_rd_out[46]
    DIRECTION OUTPUT ;
    USE SIGNAL ;
    SHAPE ABUTMENT ;
    PORT
      LAYER met2 ;
      RECT 2.690 325.980 2.830 326.400 ;
    END
  END rw0_rd_out[46]
  PIN rw0_rd_out[47]
    DIRECTION OUTPUT ;
    USE SIGNAL ;
    SHAPE ABUTMENT ;
    PORT
      LAYER met2 ;
      RECT 16.490 325.980 16.630 326.400 ;
    END
  END rw0_rd_out[47]
  PIN rw0_rd_out[48]
    DIRECTION OUTPUT ;
    USE SIGNAL ;
    SHAPE ABUTMENT ;
    PORT
      LAYER met2 ;
      RECT 30.290 325.980 30.430 326.400 ;
    END
  END rw0_rd_out[48]
  PIN rw0_rd_out[49]
    DIRECTION OUTPUT ;
    USE SIGNAL ;
    SHAPE ABUTMENT ;
    PORT
      LAYER met2 ;
      RECT 44.090 325.980 44.230 326.400 ;
    END
  END rw0_rd_out[49]
  PIN rw0_rd_out[50]
    DIRECTION OUTPUT ;
    USE SIGNAL ;
    SHAPE ABUTMENT ;
    PORT
      LAYER met2 ;
      RECT 57.890 325.980 58.030 326.400 ;
    END
  END rw0_rd_out[50]
  PIN rw0_rd_out[51]
    DIRECTION OUTPUT ;
    USE SIGNAL ;
    SHAPE ABUTMENT ;
    PORT
      LAYER met2 ;
      RECT 71.690 325.980 71.830 326.400 ;
    END
  END rw0_rd_out[51]
  PIN rw0_rd_out[52]
    DIRECTION OUTPUT ;
    USE SIGNAL ;
    SHAPE ABUTMENT ;
    PORT
      LAYER met2 ;
      RECT 85.490 325.980 85.630 326.400 ;
    END
  END rw0_rd_out[52]
  PIN rw0_rd_out[53]
    DIRECTION OUTPUT ;
    USE SIGNAL ;
    SHAPE ABUTMENT ;
    PORT
      LAYER met2 ;
      RECT 99.290 325.980 99.430 326.400 ;
    END
  END rw0_rd_out[53]
  PIN rw0_rd_out[54]
    DIRECTION OUTPUT ;
    USE SIGNAL ;
    SHAPE ABUTMENT ;
    PORT
      LAYER met2 ;
      RECT 113.090 325.980 113.230 326.400 ;
    END
  END rw0_rd_out[54]
  PIN rw0_rd_out[55]
    DIRECTION OUTPUT ;
    USE SIGNAL ;
    SHAPE ABUTMENT ;
    PORT
      LAYER met2 ;
      RECT 126.890 325.980 127.030 326.400 ;
    END
  END rw0_rd_out[55]
  PIN rw0_rd_out[56]
    DIRECTION OUTPUT ;
    USE SIGNAL ;
    SHAPE ABUTMENT ;
    PORT
      LAYER met2 ;
      RECT 140.690 325.980 140.830 326.400 ;
    END
  END rw0_rd_out[56]
  PIN rw0_rd_out[57]
    DIRECTION OUTPUT ;
    USE SIGNAL ;
    SHAPE ABUTMENT ;
    PORT
      LAYER met2 ;
      RECT 154.490 325.980 154.630 326.400 ;
    END
  END rw0_rd_out[57]
  PIN rw0_rd_out[58]
    DIRECTION OUTPUT ;
    USE SIGNAL ;
    SHAPE ABUTMENT ;
    PORT
      LAYER met2 ;
      RECT 168.290 325.980 168.430 326.400 ;
    END
  END rw0_rd_out[58]
  PIN rw0_rd_out[59]
    DIRECTION OUTPUT ;
    USE SIGNAL ;
    SHAPE ABUTMENT ;
    PORT
      LAYER met2 ;
      RECT 182.090 325.980 182.230 326.400 ;
    END
  END rw0_rd_out[59]
  PIN rw0_rd_out[60]
    DIRECTION OUTPUT ;
    USE SIGNAL ;
    SHAPE ABUTMENT ;
    PORT
      LAYER met2 ;
      RECT 195.890 325.980 196.030 326.400 ;
    END
  END rw0_rd_out[60]
  PIN rw0_rd_out[61]
    DIRECTION OUTPUT ;
    USE SIGNAL ;
    SHAPE ABUTMENT ;
    PORT
      LAYER met2 ;
      RECT 209.690 325.980 209.830 326.400 ;
    END
  END rw0_rd_out[61]
  PIN rw0_rd_out[62]
    DIRECTION OUTPUT ;
    USE SIGNAL ;
    SHAPE ABUTMENT ;
    PORT
      LAYER met2 ;
      RECT 223.490 325.980 223.630 326.400 ;
    END
  END rw0_rd_out[62]
  PIN rw0_rd_out[63]
    DIRECTION OUTPUT ;
    USE SIGNAL ;
    SHAPE ABUTMENT ;
    PORT
      LAYER met2 ;
      RECT 237.290 325.980 237.430 326.400 ;
    END
  END rw0_rd_out[63]
  PIN rw0_rd_out[64]
    DIRECTION OUTPUT ;
    USE SIGNAL ;
    SHAPE ABUTMENT ;
    PORT
      LAYER met2 ;
      RECT 251.090 325.980 251.230 326.400 ;
    END
  END rw0_rd_out[64]
  PIN rw0_rd_out[65]
    DIRECTION OUTPUT ;
    USE SIGNAL ;
    SHAPE ABUTMENT ;
    PORT
      LAYER met2 ;
      RECT 264.890 325.980 265.030 326.400 ;
    END
  END rw0_rd_out[65]
  PIN rw0_rd_out[66]
    DIRECTION OUTPUT ;
    USE SIGNAL ;
    SHAPE ABUTMENT ;
    PORT
      LAYER met2 ;
      RECT 278.690 325.980 278.830 326.400 ;
    END
  END rw0_rd_out[66]
  PIN rw0_rd_out[67]
    DIRECTION OUTPUT ;
    USE SIGNAL ;
    SHAPE ABUTMENT ;
    PORT
      LAYER met2 ;
      RECT 292.490 325.980 292.630 326.400 ;
    END
  END rw0_rd_out[67]
  PIN rw0_rd_out[68]
    DIRECTION OUTPUT ;
    USE SIGNAL ;
    SHAPE ABUTMENT ;
    PORT
      LAYER met2 ;
      RECT 306.290 325.980 306.430 326.400 ;
    END
  END rw0_rd_out[68]
  PIN rw0_rd_out[69]
    DIRECTION OUTPUT ;
    USE SIGNAL ;
    SHAPE ABUTMENT ;
    PORT
      LAYER met2 ;
      RECT 320.090 325.980 320.230 326.400 ;
    END
  END rw0_rd_out[69]
  PIN rw0_rd_out[70]
    DIRECTION OUTPUT ;
    USE SIGNAL ;
    SHAPE ABUTMENT ;
    PORT
      LAYER met2 ;
      RECT 333.890 325.980 334.030 326.400 ;
    END
  END rw0_rd_out[70]
  PIN rw0_rd_out[71]
    DIRECTION OUTPUT ;
    USE SIGNAL ;
    SHAPE ABUTMENT ;
    PORT
      LAYER met2 ;
      RECT 347.690 325.980 347.830 326.400 ;
    END
  END rw0_rd_out[71]
  PIN rw0_rd_out[72]
    DIRECTION OUTPUT ;
    USE SIGNAL ;
    SHAPE ABUTMENT ;
    PORT
      LAYER met2 ;
      RECT 361.490 325.980 361.630 326.400 ;
    END
  END rw0_rd_out[72]
  PIN rw0_rd_out[73]
    DIRECTION OUTPUT ;
    USE SIGNAL ;
    SHAPE ABUTMENT ;
    PORT
      LAYER met2 ;
      RECT 375.290 325.980 375.430 326.400 ;
    END
  END rw0_rd_out[73]
  PIN rw0_rd_out[74]
    DIRECTION OUTPUT ;
    USE SIGNAL ;
    SHAPE ABUTMENT ;
    PORT
      LAYER met2 ;
      RECT 389.090 325.980 389.230 326.400 ;
    END
  END rw0_rd_out[74]
  PIN rw0_rd_out[75]
    DIRECTION OUTPUT ;
    USE SIGNAL ;
    SHAPE ABUTMENT ;
    PORT
      LAYER met2 ;
      RECT 402.890 325.980 403.030 326.400 ;
    END
  END rw0_rd_out[75]
  PIN rw0_rd_out[76]
    DIRECTION OUTPUT ;
    USE SIGNAL ;
    SHAPE ABUTMENT ;
    PORT
      LAYER met2 ;
      RECT 416.690 325.980 416.830 326.400 ;
    END
  END rw0_rd_out[76]
  PIN rw0_rd_out[77]
    DIRECTION OUTPUT ;
    USE SIGNAL ;
    SHAPE ABUTMENT ;
    PORT
      LAYER met2 ;
      RECT 430.490 325.980 430.630 326.400 ;
    END
  END rw0_rd_out[77]
  PIN rw0_rd_out[78]
    DIRECTION OUTPUT ;
    USE SIGNAL ;
    SHAPE ABUTMENT ;
    PORT
      LAYER met2 ;
      RECT 444.290 325.980 444.430 326.400 ;
    END
  END rw0_rd_out[78]
  PIN rw0_rd_out[79]
    DIRECTION OUTPUT ;
    USE SIGNAL ;
    SHAPE ABUTMENT ;
    PORT
      LAYER met2 ;
      RECT 458.090 325.980 458.230 326.400 ;
    END
  END rw0_rd_out[79]
  PIN rw0_rd_out[80]
    DIRECTION OUTPUT ;
    USE SIGNAL ;
    SHAPE ABUTMENT ;
    PORT
      LAYER met2 ;
      RECT 471.890 325.980 472.030 326.400 ;
    END
  END rw0_rd_out[80]
  PIN rw0_rd_out[81]
    DIRECTION OUTPUT ;
    USE SIGNAL ;
    SHAPE ABUTMENT ;
    PORT
      LAYER met2 ;
      RECT 485.690 325.980 485.830 326.400 ;
    END
  END rw0_rd_out[81]
  PIN rw0_rd_out[82]
    DIRECTION OUTPUT ;
    USE SIGNAL ;
    SHAPE ABUTMENT ;
    PORT
      LAYER met2 ;
      RECT 499.490 325.980 499.630 326.400 ;
    END
  END rw0_rd_out[82]
  PIN rw0_rd_out[83]
    DIRECTION OUTPUT ;
    USE SIGNAL ;
    SHAPE ABUTMENT ;
    PORT
      LAYER met2 ;
      RECT 513.290 325.980 513.430 326.400 ;
    END
  END rw0_rd_out[83]
  PIN rw0_rd_out[84]
    DIRECTION OUTPUT ;
    USE SIGNAL ;
    SHAPE ABUTMENT ;
    PORT
      LAYER met2 ;
      RECT 527.090 325.980 527.230 326.400 ;
    END
  END rw0_rd_out[84]
  PIN rw0_rd_out[85]
    DIRECTION OUTPUT ;
    USE SIGNAL ;
    SHAPE ABUTMENT ;
    PORT
      LAYER met2 ;
      RECT 540.890 325.980 541.030 326.400 ;
    END
  END rw0_rd_out[85]
  PIN rw0_rd_out[86]
    DIRECTION OUTPUT ;
    USE SIGNAL ;
    SHAPE ABUTMENT ;
    PORT
      LAYER met2 ;
      RECT 554.690 325.980 554.830 326.400 ;
    END
  END rw0_rd_out[86]
  PIN rw0_rd_out[87]
    DIRECTION OUTPUT ;
    USE SIGNAL ;
    SHAPE ABUTMENT ;
    PORT
      LAYER met2 ;
      RECT 568.490 325.980 568.630 326.400 ;
    END
  END rw0_rd_out[87]
  PIN rw0_rd_out[88]
    DIRECTION OUTPUT ;
    USE SIGNAL ;
    SHAPE ABUTMENT ;
    PORT
      LAYER met2 ;
      RECT 582.290 325.980 582.430 326.400 ;
    END
  END rw0_rd_out[88]
  PIN rw0_rd_out[89]
    DIRECTION OUTPUT ;
    USE SIGNAL ;
    SHAPE ABUTMENT ;
    PORT
      LAYER met2 ;
      RECT 596.090 325.980 596.230 326.400 ;
    END
  END rw0_rd_out[89]
  PIN rw0_rd_out[90]
    DIRECTION OUTPUT ;
    USE SIGNAL ;
    SHAPE ABUTMENT ;
    PORT
      LAYER met2 ;
      RECT 609.890 325.980 610.030 326.400 ;
    END
  END rw0_rd_out[90]
  PIN rw0_rd_out[91]
    DIRECTION OUTPUT ;
    USE SIGNAL ;
    SHAPE ABUTMENT ;
    PORT
      LAYER met2 ;
      RECT 623.690 325.980 623.830 326.400 ;
    END
  END rw0_rd_out[91]
  PIN r0_rd_out[0]
    DIRECTION OUTPUT ;
    USE SIGNAL ;
    SHAPE ABUTMENT ;
    PORT
      LAYER met2 ;
      RECT 891.410 0.000 891.550 0.420 ;
    END
  END r0_rd_out[0]
  PIN r0_rd_out[1]
    DIRECTION OUTPUT ;
    USE SIGNAL ;
    SHAPE ABUTMENT ;
    PORT
      LAYER met2 ;
      RECT 901.070 0.000 901.210 0.420 ;
    END
  END r0_rd_out[1]
  PIN r0_rd_out[2]
    DIRECTION OUTPUT ;
    USE SIGNAL ;
    SHAPE ABUTMENT ;
    PORT
      LAYER met2 ;
      RECT 910.730 0.000 910.870 0.420 ;
    END
  END r0_rd_out[2]
  PIN r0_rd_out[3]
    DIRECTION OUTPUT ;
    USE SIGNAL ;
    SHAPE ABUTMENT ;
    PORT
      LAYER met2 ;
      RECT 920.390 0.000 920.530 0.420 ;
    END
  END r0_rd_out[3]
  PIN r0_rd_out[4]
    DIRECTION OUTPUT ;
    USE SIGNAL ;
    SHAPE ABUTMENT ;
    PORT
      LAYER met2 ;
      RECT 930.050 0.000 930.190 0.420 ;
    END
  END r0_rd_out[4]
  PIN r0_rd_out[5]
    DIRECTION OUTPUT ;
    USE SIGNAL ;
    SHAPE ABUTMENT ;
    PORT
      LAYER met2 ;
      RECT 939.710 0.000 939.850 0.420 ;
    END
  END r0_rd_out[5]
  PIN r0_rd_out[6]
    DIRECTION OUTPUT ;
    USE SIGNAL ;
    SHAPE ABUTMENT ;
    PORT
      LAYER met2 ;
      RECT 949.370 0.000 949.510 0.420 ;
    END
  END r0_rd_out[6]
  PIN r0_rd_out[7]
    DIRECTION OUTPUT ;
    USE SIGNAL ;
    SHAPE ABUTMENT ;
    PORT
      LAYER met2 ;
      RECT 959.030 0.000 959.170 0.420 ;
    END
  END r0_rd_out[7]
  PIN r0_rd_out[8]
    DIRECTION OUTPUT ;
    USE SIGNAL ;
    SHAPE ABUTMENT ;
    PORT
      LAYER met2 ;
      RECT 968.690 0.000 968.830 0.420 ;
    END
  END r0_rd_out[8]
  PIN r0_rd_out[9]
    DIRECTION OUTPUT ;
    USE SIGNAL ;
    SHAPE ABUTMENT ;
    PORT
      LAYER met2 ;
      RECT 978.350 0.000 978.490 0.420 ;
    END
  END r0_rd_out[9]
  PIN r0_rd_out[10]
    DIRECTION OUTPUT ;
    USE SIGNAL ;
    SHAPE ABUTMENT ;
    PORT
      LAYER met2 ;
      RECT 988.010 0.000 988.150 0.420 ;
    END
  END r0_rd_out[10]
  PIN r0_rd_out[11]
    DIRECTION OUTPUT ;
    USE SIGNAL ;
    SHAPE ABUTMENT ;
    PORT
      LAYER met2 ;
      RECT 997.670 0.000 997.810 0.420 ;
    END
  END r0_rd_out[11]
  PIN r0_rd_out[12]
    DIRECTION OUTPUT ;
    USE SIGNAL ;
    SHAPE ABUTMENT ;
    PORT
      LAYER met2 ;
      RECT 1007.330 0.000 1007.470 0.420 ;
    END
  END r0_rd_out[12]
  PIN r0_rd_out[13]
    DIRECTION OUTPUT ;
    USE SIGNAL ;
    SHAPE ABUTMENT ;
    PORT
      LAYER met2 ;
      RECT 1016.990 0.000 1017.130 0.420 ;
    END
  END r0_rd_out[13]
  PIN r0_rd_out[14]
    DIRECTION OUTPUT ;
    USE SIGNAL ;
    SHAPE ABUTMENT ;
    PORT
      LAYER met2 ;
      RECT 1026.650 0.000 1026.790 0.420 ;
    END
  END r0_rd_out[14]
  PIN r0_rd_out[15]
    DIRECTION OUTPUT ;
    USE SIGNAL ;
    SHAPE ABUTMENT ;
    PORT
      LAYER met2 ;
      RECT 1036.310 0.000 1036.450 0.420 ;
    END
  END r0_rd_out[15]
  PIN r0_rd_out[16]
    DIRECTION OUTPUT ;
    USE SIGNAL ;
    SHAPE ABUTMENT ;
    PORT
      LAYER met2 ;
      RECT 1045.970 0.000 1046.110 0.420 ;
    END
  END r0_rd_out[16]
  PIN r0_rd_out[17]
    DIRECTION OUTPUT ;
    USE SIGNAL ;
    SHAPE ABUTMENT ;
    PORT
      LAYER met2 ;
      RECT 1055.630 0.000 1055.770 0.420 ;
    END
  END r0_rd_out[17]
  PIN r0_rd_out[18]
    DIRECTION OUTPUT ;
    USE SIGNAL ;
    SHAPE ABUTMENT ;
    PORT
      LAYER met2 ;
      RECT 1065.290 0.000 1065.430 0.420 ;
    END
  END r0_rd_out[18]
  PIN r0_rd_out[19]
    DIRECTION OUTPUT ;
    USE SIGNAL ;
    SHAPE ABUTMENT ;
    PORT
      LAYER met2 ;
      RECT 1074.950 0.000 1075.090 0.420 ;
    END
  END r0_rd_out[19]
  PIN r0_rd_out[20]
    DIRECTION OUTPUT ;
    USE SIGNAL ;
    SHAPE ABUTMENT ;
    PORT
      LAYER met2 ;
      RECT 1084.610 0.000 1084.750 0.420 ;
    END
  END r0_rd_out[20]
  PIN r0_rd_out[21]
    DIRECTION OUTPUT ;
    USE SIGNAL ;
    SHAPE ABUTMENT ;
    PORT
      LAYER met2 ;
      RECT 1094.270 0.000 1094.410 0.420 ;
    END
  END r0_rd_out[21]
  PIN r0_rd_out[22]
    DIRECTION OUTPUT ;
    USE SIGNAL ;
    SHAPE ABUTMENT ;
    PORT
      LAYER met2 ;
      RECT 1103.930 0.000 1104.070 0.420 ;
    END
  END r0_rd_out[22]
  PIN r0_rd_out[23]
    DIRECTION OUTPUT ;
    USE SIGNAL ;
    SHAPE ABUTMENT ;
    PORT
      LAYER met2 ;
      RECT 1113.590 0.000 1113.730 0.420 ;
    END
  END r0_rd_out[23]
  PIN r0_rd_out[24]
    DIRECTION OUTPUT ;
    USE SIGNAL ;
    SHAPE ABUTMENT ;
    PORT
      LAYER met2 ;
      RECT 1123.250 0.000 1123.390 0.420 ;
    END
  END r0_rd_out[24]
  PIN r0_rd_out[25]
    DIRECTION OUTPUT ;
    USE SIGNAL ;
    SHAPE ABUTMENT ;
    PORT
      LAYER met2 ;
      RECT 1132.910 0.000 1133.050 0.420 ;
    END
  END r0_rd_out[25]
  PIN r0_rd_out[26]
    DIRECTION OUTPUT ;
    USE SIGNAL ;
    SHAPE ABUTMENT ;
    PORT
      LAYER met2 ;
      RECT 1142.570 0.000 1142.710 0.420 ;
    END
  END r0_rd_out[26]
  PIN r0_rd_out[27]
    DIRECTION OUTPUT ;
    USE SIGNAL ;
    SHAPE ABUTMENT ;
    PORT
      LAYER met2 ;
      RECT 1152.230 0.000 1152.370 0.420 ;
    END
  END r0_rd_out[27]
  PIN r0_rd_out[28]
    DIRECTION OUTPUT ;
    USE SIGNAL ;
    SHAPE ABUTMENT ;
    PORT
      LAYER met2 ;
      RECT 1161.890 0.000 1162.030 0.420 ;
    END
  END r0_rd_out[28]
  PIN r0_rd_out[29]
    DIRECTION OUTPUT ;
    USE SIGNAL ;
    SHAPE ABUTMENT ;
    PORT
      LAYER met2 ;
      RECT 1171.550 0.000 1171.690 0.420 ;
    END
  END r0_rd_out[29]
  PIN r0_rd_out[30]
    DIRECTION OUTPUT ;
    USE SIGNAL ;
    SHAPE ABUTMENT ;
    PORT
      LAYER met2 ;
      RECT 1181.210 0.000 1181.350 0.420 ;
    END
  END r0_rd_out[30]
  PIN r0_rd_out[31]
    DIRECTION OUTPUT ;
    USE SIGNAL ;
    SHAPE ABUTMENT ;
    PORT
      LAYER met2 ;
      RECT 1190.870 0.000 1191.010 0.420 ;
    END
  END r0_rd_out[31]
  PIN r0_rd_out[32]
    DIRECTION OUTPUT ;
    USE SIGNAL ;
    SHAPE ABUTMENT ;
    PORT
      LAYER met2 ;
      RECT 1200.530 0.000 1200.670 0.420 ;
    END
  END r0_rd_out[32]
  PIN r0_rd_out[33]
    DIRECTION OUTPUT ;
    USE SIGNAL ;
    SHAPE ABUTMENT ;
    PORT
      LAYER met2 ;
      RECT 1210.190 0.000 1210.330 0.420 ;
    END
  END r0_rd_out[33]
  PIN r0_rd_out[34]
    DIRECTION OUTPUT ;
    USE SIGNAL ;
    SHAPE ABUTMENT ;
    PORT
      LAYER met2 ;
      RECT 1219.850 0.000 1219.990 0.420 ;
    END
  END r0_rd_out[34]
  PIN r0_rd_out[35]
    DIRECTION OUTPUT ;
    USE SIGNAL ;
    SHAPE ABUTMENT ;
    PORT
      LAYER met2 ;
      RECT 1229.510 0.000 1229.650 0.420 ;
    END
  END r0_rd_out[35]
  PIN r0_rd_out[36]
    DIRECTION OUTPUT ;
    USE SIGNAL ;
    SHAPE ABUTMENT ;
    PORT
      LAYER met2 ;
      RECT 1239.170 0.000 1239.310 0.420 ;
    END
  END r0_rd_out[36]
  PIN r0_rd_out[37]
    DIRECTION OUTPUT ;
    USE SIGNAL ;
    SHAPE ABUTMENT ;
    PORT
      LAYER met2 ;
      RECT 1248.830 0.000 1248.970 0.420 ;
    END
  END r0_rd_out[37]
  PIN r0_rd_out[38]
    DIRECTION OUTPUT ;
    USE SIGNAL ;
    SHAPE ABUTMENT ;
    PORT
      LAYER met2 ;
      RECT 1258.490 0.000 1258.630 0.420 ;
    END
  END r0_rd_out[38]
  PIN r0_rd_out[39]
    DIRECTION OUTPUT ;
    USE SIGNAL ;
    SHAPE ABUTMENT ;
    PORT
      LAYER met2 ;
      RECT 1268.150 0.000 1268.290 0.420 ;
    END
  END r0_rd_out[39]
  PIN r0_rd_out[40]
    DIRECTION OUTPUT ;
    USE SIGNAL ;
    SHAPE ABUTMENT ;
    PORT
      LAYER met2 ;
      RECT 1277.810 0.000 1277.950 0.420 ;
    END
  END r0_rd_out[40]
  PIN r0_rd_out[41]
    DIRECTION OUTPUT ;
    USE SIGNAL ;
    SHAPE ABUTMENT ;
    PORT
      LAYER met2 ;
      RECT 1287.470 0.000 1287.610 0.420 ;
    END
  END r0_rd_out[41]
  PIN r0_rd_out[42]
    DIRECTION OUTPUT ;
    USE SIGNAL ;
    SHAPE ABUTMENT ;
    PORT
      LAYER met2 ;
      RECT 1297.130 0.000 1297.270 0.420 ;
    END
  END r0_rd_out[42]
  PIN r0_rd_out[43]
    DIRECTION OUTPUT ;
    USE SIGNAL ;
    SHAPE ABUTMENT ;
    PORT
      LAYER met2 ;
      RECT 1306.790 0.000 1306.930 0.420 ;
    END
  END r0_rd_out[43]
  PIN r0_rd_out[44]
    DIRECTION OUTPUT ;
    USE SIGNAL ;
    SHAPE ABUTMENT ;
    PORT
      LAYER met2 ;
      RECT 1316.450 0.000 1316.590 0.420 ;
    END
  END r0_rd_out[44]
  PIN r0_rd_out[45]
    DIRECTION OUTPUT ;
    USE SIGNAL ;
    SHAPE ABUTMENT ;
    PORT
      LAYER met2 ;
      RECT 1326.110 0.000 1326.250 0.420 ;
    END
  END r0_rd_out[45]
  PIN r0_rd_out[46]
    DIRECTION OUTPUT ;
    USE SIGNAL ;
    SHAPE ABUTMENT ;
    PORT
      LAYER met2 ;
      RECT 637.490 325.980 637.630 326.400 ;
    END
  END r0_rd_out[46]
  PIN r0_rd_out[47]
    DIRECTION OUTPUT ;
    USE SIGNAL ;
    SHAPE ABUTMENT ;
    PORT
      LAYER met2 ;
      RECT 651.290 325.980 651.430 326.400 ;
    END
  END r0_rd_out[47]
  PIN r0_rd_out[48]
    DIRECTION OUTPUT ;
    USE SIGNAL ;
    SHAPE ABUTMENT ;
    PORT
      LAYER met2 ;
      RECT 665.090 325.980 665.230 326.400 ;
    END
  END r0_rd_out[48]
  PIN r0_rd_out[49]
    DIRECTION OUTPUT ;
    USE SIGNAL ;
    SHAPE ABUTMENT ;
    PORT
      LAYER met2 ;
      RECT 678.890 325.980 679.030 326.400 ;
    END
  END r0_rd_out[49]
  PIN r0_rd_out[50]
    DIRECTION OUTPUT ;
    USE SIGNAL ;
    SHAPE ABUTMENT ;
    PORT
      LAYER met2 ;
      RECT 692.690 325.980 692.830 326.400 ;
    END
  END r0_rd_out[50]
  PIN r0_rd_out[51]
    DIRECTION OUTPUT ;
    USE SIGNAL ;
    SHAPE ABUTMENT ;
    PORT
      LAYER met2 ;
      RECT 706.490 325.980 706.630 326.400 ;
    END
  END r0_rd_out[51]
  PIN r0_rd_out[52]
    DIRECTION OUTPUT ;
    USE SIGNAL ;
    SHAPE ABUTMENT ;
    PORT
      LAYER met2 ;
      RECT 720.290 325.980 720.430 326.400 ;
    END
  END r0_rd_out[52]
  PIN r0_rd_out[53]
    DIRECTION OUTPUT ;
    USE SIGNAL ;
    SHAPE ABUTMENT ;
    PORT
      LAYER met2 ;
      RECT 734.090 325.980 734.230 326.400 ;
    END
  END r0_rd_out[53]
  PIN r0_rd_out[54]
    DIRECTION OUTPUT ;
    USE SIGNAL ;
    SHAPE ABUTMENT ;
    PORT
      LAYER met2 ;
      RECT 747.890 325.980 748.030 326.400 ;
    END
  END r0_rd_out[54]
  PIN r0_rd_out[55]
    DIRECTION OUTPUT ;
    USE SIGNAL ;
    SHAPE ABUTMENT ;
    PORT
      LAYER met2 ;
      RECT 761.690 325.980 761.830 326.400 ;
    END
  END r0_rd_out[55]
  PIN r0_rd_out[56]
    DIRECTION OUTPUT ;
    USE SIGNAL ;
    SHAPE ABUTMENT ;
    PORT
      LAYER met2 ;
      RECT 775.490 325.980 775.630 326.400 ;
    END
  END r0_rd_out[56]
  PIN r0_rd_out[57]
    DIRECTION OUTPUT ;
    USE SIGNAL ;
    SHAPE ABUTMENT ;
    PORT
      LAYER met2 ;
      RECT 789.290 325.980 789.430 326.400 ;
    END
  END r0_rd_out[57]
  PIN r0_rd_out[58]
    DIRECTION OUTPUT ;
    USE SIGNAL ;
    SHAPE ABUTMENT ;
    PORT
      LAYER met2 ;
      RECT 803.090 325.980 803.230 326.400 ;
    END
  END r0_rd_out[58]
  PIN r0_rd_out[59]
    DIRECTION OUTPUT ;
    USE SIGNAL ;
    SHAPE ABUTMENT ;
    PORT
      LAYER met2 ;
      RECT 816.890 325.980 817.030 326.400 ;
    END
  END r0_rd_out[59]
  PIN r0_rd_out[60]
    DIRECTION OUTPUT ;
    USE SIGNAL ;
    SHAPE ABUTMENT ;
    PORT
      LAYER met2 ;
      RECT 830.690 325.980 830.830 326.400 ;
    END
  END r0_rd_out[60]
  PIN r0_rd_out[61]
    DIRECTION OUTPUT ;
    USE SIGNAL ;
    SHAPE ABUTMENT ;
    PORT
      LAYER met2 ;
      RECT 844.490 325.980 844.630 326.400 ;
    END
  END r0_rd_out[61]
  PIN r0_rd_out[62]
    DIRECTION OUTPUT ;
    USE SIGNAL ;
    SHAPE ABUTMENT ;
    PORT
      LAYER met2 ;
      RECT 858.290 325.980 858.430 326.400 ;
    END
  END r0_rd_out[62]
  PIN r0_rd_out[63]
    DIRECTION OUTPUT ;
    USE SIGNAL ;
    SHAPE ABUTMENT ;
    PORT
      LAYER met2 ;
      RECT 872.090 325.980 872.230 326.400 ;
    END
  END r0_rd_out[63]
  PIN r0_rd_out[64]
    DIRECTION OUTPUT ;
    USE SIGNAL ;
    SHAPE ABUTMENT ;
    PORT
      LAYER met2 ;
      RECT 885.890 325.980 886.030 326.400 ;
    END
  END r0_rd_out[64]
  PIN r0_rd_out[65]
    DIRECTION OUTPUT ;
    USE SIGNAL ;
    SHAPE ABUTMENT ;
    PORT
      LAYER met2 ;
      RECT 899.690 325.980 899.830 326.400 ;
    END
  END r0_rd_out[65]
  PIN r0_rd_out[66]
    DIRECTION OUTPUT ;
    USE SIGNAL ;
    SHAPE ABUTMENT ;
    PORT
      LAYER met2 ;
      RECT 913.490 325.980 913.630 326.400 ;
    END
  END r0_rd_out[66]
  PIN r0_rd_out[67]
    DIRECTION OUTPUT ;
    USE SIGNAL ;
    SHAPE ABUTMENT ;
    PORT
      LAYER met2 ;
      RECT 927.290 325.980 927.430 326.400 ;
    END
  END r0_rd_out[67]
  PIN r0_rd_out[68]
    DIRECTION OUTPUT ;
    USE SIGNAL ;
    SHAPE ABUTMENT ;
    PORT
      LAYER met2 ;
      RECT 941.090 325.980 941.230 326.400 ;
    END
  END r0_rd_out[68]
  PIN r0_rd_out[69]
    DIRECTION OUTPUT ;
    USE SIGNAL ;
    SHAPE ABUTMENT ;
    PORT
      LAYER met2 ;
      RECT 954.890 325.980 955.030 326.400 ;
    END
  END r0_rd_out[69]
  PIN r0_rd_out[70]
    DIRECTION OUTPUT ;
    USE SIGNAL ;
    SHAPE ABUTMENT ;
    PORT
      LAYER met2 ;
      RECT 968.690 325.980 968.830 326.400 ;
    END
  END r0_rd_out[70]
  PIN r0_rd_out[71]
    DIRECTION OUTPUT ;
    USE SIGNAL ;
    SHAPE ABUTMENT ;
    PORT
      LAYER met2 ;
      RECT 982.490 325.980 982.630 326.400 ;
    END
  END r0_rd_out[71]
  PIN r0_rd_out[72]
    DIRECTION OUTPUT ;
    USE SIGNAL ;
    SHAPE ABUTMENT ;
    PORT
      LAYER met2 ;
      RECT 996.290 325.980 996.430 326.400 ;
    END
  END r0_rd_out[72]
  PIN r0_rd_out[73]
    DIRECTION OUTPUT ;
    USE SIGNAL ;
    SHAPE ABUTMENT ;
    PORT
      LAYER met2 ;
      RECT 1010.090 325.980 1010.230 326.400 ;
    END
  END r0_rd_out[73]
  PIN r0_rd_out[74]
    DIRECTION OUTPUT ;
    USE SIGNAL ;
    SHAPE ABUTMENT ;
    PORT
      LAYER met2 ;
      RECT 1023.890 325.980 1024.030 326.400 ;
    END
  END r0_rd_out[74]
  PIN r0_rd_out[75]
    DIRECTION OUTPUT ;
    USE SIGNAL ;
    SHAPE ABUTMENT ;
    PORT
      LAYER met2 ;
      RECT 1037.690 325.980 1037.830 326.400 ;
    END
  END r0_rd_out[75]
  PIN r0_rd_out[76]
    DIRECTION OUTPUT ;
    USE SIGNAL ;
    SHAPE ABUTMENT ;
    PORT
      LAYER met2 ;
      RECT 1051.490 325.980 1051.630 326.400 ;
    END
  END r0_rd_out[76]
  PIN r0_rd_out[77]
    DIRECTION OUTPUT ;
    USE SIGNAL ;
    SHAPE ABUTMENT ;
    PORT
      LAYER met2 ;
      RECT 1065.290 325.980 1065.430 326.400 ;
    END
  END r0_rd_out[77]
  PIN r0_rd_out[78]
    DIRECTION OUTPUT ;
    USE SIGNAL ;
    SHAPE ABUTMENT ;
    PORT
      LAYER met2 ;
      RECT 1079.090 325.980 1079.230 326.400 ;
    END
  END r0_rd_out[78]
  PIN r0_rd_out[79]
    DIRECTION OUTPUT ;
    USE SIGNAL ;
    SHAPE ABUTMENT ;
    PORT
      LAYER met2 ;
      RECT 1092.890 325.980 1093.030 326.400 ;
    END
  END r0_rd_out[79]
  PIN r0_rd_out[80]
    DIRECTION OUTPUT ;
    USE SIGNAL ;
    SHAPE ABUTMENT ;
    PORT
      LAYER met2 ;
      RECT 1106.690 325.980 1106.830 326.400 ;
    END
  END r0_rd_out[80]
  PIN r0_rd_out[81]
    DIRECTION OUTPUT ;
    USE SIGNAL ;
    SHAPE ABUTMENT ;
    PORT
      LAYER met2 ;
      RECT 1120.490 325.980 1120.630 326.400 ;
    END
  END r0_rd_out[81]
  PIN r0_rd_out[82]
    DIRECTION OUTPUT ;
    USE SIGNAL ;
    SHAPE ABUTMENT ;
    PORT
      LAYER met2 ;
      RECT 1134.290 325.980 1134.430 326.400 ;
    END
  END r0_rd_out[82]
  PIN r0_rd_out[83]
    DIRECTION OUTPUT ;
    USE SIGNAL ;
    SHAPE ABUTMENT ;
    PORT
      LAYER met2 ;
      RECT 1148.090 325.980 1148.230 326.400 ;
    END
  END r0_rd_out[83]
  PIN r0_rd_out[84]
    DIRECTION OUTPUT ;
    USE SIGNAL ;
    SHAPE ABUTMENT ;
    PORT
      LAYER met2 ;
      RECT 1161.890 325.980 1162.030 326.400 ;
    END
  END r0_rd_out[84]
  PIN r0_rd_out[85]
    DIRECTION OUTPUT ;
    USE SIGNAL ;
    SHAPE ABUTMENT ;
    PORT
      LAYER met2 ;
      RECT 1175.690 325.980 1175.830 326.400 ;
    END
  END r0_rd_out[85]
  PIN r0_rd_out[86]
    DIRECTION OUTPUT ;
    USE SIGNAL ;
    SHAPE ABUTMENT ;
    PORT
      LAYER met2 ;
      RECT 1189.490 325.980 1189.630 326.400 ;
    END
  END r0_rd_out[86]
  PIN r0_rd_out[87]
    DIRECTION OUTPUT ;
    USE SIGNAL ;
    SHAPE ABUTMENT ;
    PORT
      LAYER met2 ;
      RECT 1203.290 325.980 1203.430 326.400 ;
    END
  END r0_rd_out[87]
  PIN r0_rd_out[88]
    DIRECTION OUTPUT ;
    USE SIGNAL ;
    SHAPE ABUTMENT ;
    PORT
      LAYER met2 ;
      RECT 1217.090 325.980 1217.230 326.400 ;
    END
  END r0_rd_out[88]
  PIN r0_rd_out[89]
    DIRECTION OUTPUT ;
    USE SIGNAL ;
    SHAPE ABUTMENT ;
    PORT
      LAYER met2 ;
      RECT 1230.890 325.980 1231.030 326.400 ;
    END
  END r0_rd_out[89]
  PIN r0_rd_out[90]
    DIRECTION OUTPUT ;
    USE SIGNAL ;
    SHAPE ABUTMENT ;
    PORT
      LAYER met2 ;
      RECT 1244.690 325.980 1244.830 326.400 ;
    END
  END r0_rd_out[90]
  PIN r0_rd_out[91]
    DIRECTION OUTPUT ;
    USE SIGNAL ;
    SHAPE ABUTMENT ;
    PORT
      LAYER met2 ;
      RECT 1258.490 325.980 1258.630 326.400 ;
    END
  END r0_rd_out[91]
  PIN rw0_addr_in[0]
    DIRECTION INPUT ;
    USE SIGNAL ;
    SHAPE ABUTMENT ;
    PORT
      LAYER met3 ;
      RECT 0.000 238.530 0.900 238.830 ;
    END
  END rw0_addr_in[0]
  PIN rw0_addr_in[1]
    DIRECTION INPUT ;
    USE SIGNAL ;
    SHAPE ABUTMENT ;
    PORT
      LAYER met3 ;
      RECT 0.000 248.730 0.900 249.030 ;
    END
  END rw0_addr_in[1]
  PIN rw0_addr_in[2]
    DIRECTION INPUT ;
    USE SIGNAL ;
    SHAPE ABUTMENT ;
    PORT
      LAYER met3 ;
      RECT 0.000 258.930 0.900 259.230 ;
    END
  END rw0_addr_in[2]
  PIN rw0_addr_in[3]
    DIRECTION INPUT ;
    USE SIGNAL ;
    SHAPE ABUTMENT ;
    PORT
      LAYER met3 ;
      RECT 0.000 269.130 0.900 269.430 ;
    END
  END rw0_addr_in[3]
  PIN rw0_addr_in[4]
    DIRECTION INPUT ;
    USE SIGNAL ;
    SHAPE ABUTMENT ;
    PORT
      LAYER met3 ;
      RECT 1358.400 238.530 1359.300 238.830 ;
    END
  END rw0_addr_in[4]
  PIN rw0_addr_in[5]
    DIRECTION INPUT ;
    USE SIGNAL ;
    SHAPE ABUTMENT ;
    PORT
      LAYER met3 ;
      RECT 1358.400 248.730 1359.300 249.030 ;
    END
  END rw0_addr_in[5]
  PIN rw0_addr_in[6]
    DIRECTION INPUT ;
    USE SIGNAL ;
    SHAPE ABUTMENT ;
    PORT
      LAYER met3 ;
      RECT 1358.400 258.930 1359.300 259.230 ;
    END
  END rw0_addr_in[6]
  PIN rw0_addr_in[7]
    DIRECTION INPUT ;
    USE SIGNAL ;
    SHAPE ABUTMENT ;
    PORT
      LAYER met3 ;
      RECT 1358.400 269.130 1359.300 269.430 ;
    END
  END rw0_addr_in[7]
  PIN r0_addr_in[0]
    DIRECTION INPUT ;
    USE SIGNAL ;
    SHAPE ABUTMENT ;
    PORT
      LAYER met3 ;
      RECT 0.000 279.330 0.900 279.630 ;
    END
  END r0_addr_in[0]
  PIN r0_addr_in[1]
    DIRECTION INPUT ;
    USE SIGNAL ;
    SHAPE ABUTMENT ;
    PORT
      LAYER met3 ;
      RECT 0.000 289.530 0.900 289.830 ;
    END
  END r0_addr_in[1]
  PIN r0_addr_in[2]
    DIRECTION INPUT ;
    USE SIGNAL ;
    SHAPE ABUTMENT ;
    PORT
      LAYER met3 ;
      RECT 0.000 299.730 0.900 300.030 ;
    END
  END r0_addr_in[2]
  PIN r0_addr_in[3]
    DIRECTION INPUT ;
    USE SIGNAL ;
    SHAPE ABUTMENT ;
    PORT
      LAYER met3 ;
      RECT 0.000 309.930 0.900 310.230 ;
    END
  END r0_addr_in[3]
  PIN r0_addr_in[4]
    DIRECTION INPUT ;
    USE SIGNAL ;
    SHAPE ABUTMENT ;
    PORT
      LAYER met3 ;
      RECT 1358.400 279.330 1359.300 279.630 ;
    END
  END r0_addr_in[4]
  PIN r0_addr_in[5]
    DIRECTION INPUT ;
    USE SIGNAL ;
    SHAPE ABUTMENT ;
    PORT
      LAYER met3 ;
      RECT 1358.400 289.530 1359.300 289.830 ;
    END
  END r0_addr_in[5]
  PIN r0_addr_in[6]
    DIRECTION INPUT ;
    USE SIGNAL ;
    SHAPE ABUTMENT ;
    PORT
      LAYER met3 ;
      RECT 1358.400 299.730 1359.300 300.030 ;
    END
  END r0_addr_in[6]
  PIN r0_addr_in[7]
    DIRECTION INPUT ;
    USE SIGNAL ;
    SHAPE ABUTMENT ;
    PORT
      LAYER met3 ;
      RECT 1358.400 309.930 1359.300 310.230 ;
    END
  END r0_addr_in[7]
  PIN rw0_we_in
    DIRECTION INPUT ;
    USE SIGNAL ;
    SHAPE ABUTMENT ;
    PORT
      LAYER met2 ;
      RECT 1272.290 325.980 1272.430 326.400 ;
    END
  END rw0_we_in
  PIN rw0_ce_in
    DIRECTION INPUT ;
    USE SIGNAL ;
    SHAPE ABUTMENT ;
    PORT
      LAYER met2 ;
      RECT 1286.090 325.980 1286.230 326.400 ;
    END
  END rw0_ce_in
  PIN rw0_clk
    DIRECTION INPUT ;
    USE SIGNAL ;
    SHAPE ABUTMENT ;
    PORT
      LAYER met2 ;
      RECT 1299.890 325.980 1300.030 326.400 ;
    END
  END rw0_clk
  PIN r0_ce_in
    DIRECTION INPUT ;
    USE SIGNAL ;
    SHAPE ABUTMENT ;
    PORT
      LAYER met2 ;
      RECT 1313.690 325.980 1313.830 326.400 ;
    END
  END r0_ce_in
  PIN r0_clk
    DIRECTION INPUT ;
    USE SIGNAL ;
    SHAPE ABUTMENT ;
    PORT
      LAYER met2 ;
      RECT 1327.490 325.980 1327.630 326.400 ;
    END
  END r0_clk
  PIN VSS
    DIRECTION INOUT ;
    USE GROUND ;
    PORT
      LAYER met4 ;
      RECT 2.160 4.080 3.360 322.320 ;
      RECT 13.040 4.080 14.240 322.320 ;
      RECT 23.920 4.080 25.120 322.320 ;
      RECT 34.800 4.080 36.000 322.320 ;
      RECT 45.680 4.080 46.880 322.320 ;
      RECT 56.560 4.080 57.760 322.320 ;
      RECT 67.440 4.080 68.640 322.320 ;
      RECT 78.320 4.080 79.520 322.320 ;
      RECT 89.200 4.080 90.400 322.320 ;
      RECT 100.080 4.080 101.280 322.320 ;
      RECT 110.960 4.080 112.160 322.320 ;
      RECT 121.840 4.080 123.040 322.320 ;
      RECT 132.720 4.080 133.920 322.320 ;
      RECT 143.600 4.080 144.800 322.320 ;
      RECT 154.480 4.080 155.680 322.320 ;
      RECT 165.360 4.080 166.560 322.320 ;
      RECT 176.240 4.080 177.440 322.320 ;
      RECT 187.120 4.080 188.320 322.320 ;
      RECT 198.000 4.080 199.200 322.320 ;
      RECT 208.880 4.080 210.080 322.320 ;
      RECT 219.760 4.080 220.960 322.320 ;
      RECT 230.640 4.080 231.840 322.320 ;
      RECT 241.520 4.080 242.720 322.320 ;
      RECT 252.400 4.080 253.600 322.320 ;
      RECT 263.280 4.080 264.480 322.320 ;
      RECT 274.160 4.080 275.360 322.320 ;
      RECT 285.040 4.080 286.240 322.320 ;
      RECT 295.920 4.080 297.120 322.320 ;
      RECT 306.800 4.080 308.000 322.320 ;
      RECT 317.680 4.080 318.880 322.320 ;
      RECT 328.560 4.080 329.760 322.320 ;
      RECT 339.440 4.080 340.640 322.320 ;
      RECT 350.320 4.080 351.520 322.320 ;
      RECT 361.200 4.080 362.400 322.320 ;
      RECT 372.080 4.080 373.280 322.320 ;
      RECT 382.960 4.080 384.160 322.320 ;
      RECT 393.840 4.080 395.040 322.320 ;
      RECT 404.720 4.080 405.920 322.320 ;
      RECT 415.600 4.080 416.800 322.320 ;
      RECT 426.480 4.080 427.680 322.320 ;
      RECT 437.360 4.080 438.560 322.320 ;
      RECT 448.240 4.080 449.440 322.320 ;
      RECT 459.120 4.080 460.320 322.320 ;
      RECT 470.000 4.080 471.200 322.320 ;
      RECT 480.880 4.080 482.080 322.320 ;
      RECT 491.760 4.080 492.960 322.320 ;
      RECT 502.640 4.080 503.840 322.320 ;
      RECT 513.520 4.080 514.720 322.320 ;
      RECT 524.400 4.080 525.600 322.320 ;
      RECT 535.280 4.080 536.480 322.320 ;
      RECT 546.160 4.080 547.360 322.320 ;
      RECT 557.040 4.080 558.240 322.320 ;
      RECT 567.920 4.080 569.120 322.320 ;
      RECT 578.800 4.080 580.000 322.320 ;
      RECT 589.680 4.080 590.880 322.320 ;
      RECT 600.560 4.080 601.760 322.320 ;
      RECT 611.440 4.080 612.640 322.320 ;
      RECT 622.320 4.080 623.520 322.320 ;
      RECT 633.200 4.080 634.400 322.320 ;
      RECT 644.080 4.080 645.280 322.320 ;
      RECT 654.960 4.080 656.160 322.320 ;
      RECT 665.840 4.080 667.040 322.320 ;
      RECT 676.720 4.080 677.920 322.320 ;
      RECT 687.600 4.080 688.800 322.320 ;
      RECT 698.480 4.080 699.680 322.320 ;
      RECT 709.360 4.080 710.560 322.320 ;
      RECT 720.240 4.080 721.440 322.320 ;
      RECT 731.120 4.080 732.320 322.320 ;
      RECT 742.000 4.080 743.200 322.320 ;
      RECT 752.880 4.080 754.080 322.320 ;
      RECT 763.760 4.080 764.960 322.320 ;
      RECT 774.640 4.080 775.840 322.320 ;
      RECT 785.520 4.080 786.720 322.320 ;
      RECT 796.400 4.080 797.600 322.320 ;
      RECT 807.280 4.080 808.480 322.320 ;
      RECT 818.160 4.080 819.360 322.320 ;
      RECT 829.040 4.080 830.240 322.320 ;
      RECT 839.920 4.080 841.120 322.320 ;
      RECT 850.800 4.080 852.000 322.320 ;
      RECT 861.680 4.080 862.880 322.320 ;
      RECT 872.560 4.080 873.760 322.320 ;
      RECT 883.440 4.080 884.640 322.320 ;
      RECT 894.320 4.080 895.520 322.320 ;
      RECT 905.200 4.080 906.400 322.320 ;
      RECT 916.080 4.080 917.280 322.320 ;
      RECT 926.960 4.080 928.160 322.320 ;
      RECT 937.840 4.080 939.040 322.320 ;
      RECT 948.720 4.080 949.920 322.320 ;
      RECT 959.600 4.080 960.800 322.320 ;
      RECT 970.480 4.080 971.680 322.320 ;
      RECT 981.360 4.080 982.560 322.320 ;
      RECT 992.240 4.080 993.440 322.320 ;
      RECT 1003.120 4.080 1004.320 322.320 ;
      RECT 1014.000 4.080 1015.200 322.320 ;
      RECT 1024.880 4.080 1026.080 322.320 ;
      RECT 1035.760 4.080 1036.960 322.320 ;
      RECT 1046.640 4.080 1047.840 322.320 ;
      RECT 1057.520 4.080 1058.720 322.320 ;
      RECT 1068.400 4.080 1069.600 322.320 ;
      RECT 1079.280 4.080 1080.480 322.320 ;
      RECT 1090.160 4.080 1091.360 322.320 ;
      RECT 1101.040 4.080 1102.240 322.320 ;
      RECT 1111.920 4.080 1113.120 322.320 ;
      RECT 1122.800 4.080 1124.000 322.320 ;
      RECT 1133.680 4.080 1134.880 322.320 ;
      RECT 1144.560 4.080 1145.760 322.320 ;
      RECT 1155.440 4.080 1156.640 322.320 ;
      RECT 1166.320 4.080 1167.520 322.320 ;
      RECT 1177.200 4.080 1178.400 322.320 ;
      RECT 1188.080 4.080 1189.280 322.320 ;
      RECT 1198.960 4.080 1200.160 322.320 ;
      RECT 1209.840 4.080 1211.040 322.320 ;
      RECT 1220.720 4.080 1221.920 322.320 ;
      RECT 1231.600 4.080 1232.800 322.320 ;
      RECT 1242.480 4.080 1243.680 322.320 ;
      RECT 1253.360 4.080 1254.560 322.320 ;
      RECT 1264.240 4.080 1265.440 322.320 ;
      RECT 1275.120 4.080 1276.320 322.320 ;
      RECT 1286.000 4.080 1287.200 322.320 ;
      RECT 1296.880 4.080 1298.080 322.320 ;
      RECT 1307.760 4.080 1308.960 322.320 ;
      RECT 1318.640 4.080 1319.840 322.320 ;
      RECT 1329.520 4.080 1330.720 322.320 ;
      RECT 1340.400 4.080 1341.600 322.320 ;
      RECT 1351.280 4.080 1352.480 322.320 ;
    END
  END VSS
  PIN VDD
    DIRECTION INOUT ;
    USE POWER ;
    PORT
      LAYER met4 ;
      RECT 2.160 4.080 3.360 322.320 ;
      RECT 13.040 4.080 14.240 322.320 ;
      RECT 23.920 4.080 25.120 322.320 ;
      RECT 34.800 4.080 36.000 322.320 ;
      RECT 45.680 4.080 46.880 322.320 ;
      RECT 56.560 4.080 57.760 322.320 ;
      RECT 67.440 4.080 68.640 322.320 ;
      RECT 78.320 4.080 79.520 322.320 ;
      RECT 89.200 4.080 90.400 322.320 ;
      RECT 100.080 4.080 101.280 322.320 ;
      RECT 110.960 4.080 112.160 322.320 ;
      RECT 121.840 4.080 123.040 322.320 ;
      RECT 132.720 4.080 133.920 322.320 ;
      RECT 143.600 4.080 144.800 322.320 ;
      RECT 154.480 4.080 155.680 322.320 ;
      RECT 165.360 4.080 166.560 322.320 ;
      RECT 176.240 4.080 177.440 322.320 ;
      RECT 187.120 4.080 188.320 322.320 ;
      RECT 198.000 4.080 199.200 322.320 ;
      RECT 208.880 4.080 210.080 322.320 ;
      RECT 219.760 4.080 220.960 322.320 ;
      RECT 230.640 4.080 231.840 322.320 ;
      RECT 241.520 4.080 242.720 322.320 ;
      RECT 252.400 4.080 253.600 322.320 ;
      RECT 263.280 4.080 264.480 322.320 ;
      RECT 274.160 4.080 275.360 322.320 ;
      RECT 285.040 4.080 286.240 322.320 ;
      RECT 295.920 4.080 297.120 322.320 ;
      RECT 306.800 4.080 308.000 322.320 ;
      RECT 317.680 4.080 318.880 322.320 ;
      RECT 328.560 4.080 329.760 322.320 ;
      RECT 339.440 4.080 340.640 322.320 ;
      RECT 350.320 4.080 351.520 322.320 ;
      RECT 361.200 4.080 362.400 322.320 ;
      RECT 372.080 4.080 373.280 322.320 ;
      RECT 382.960 4.080 384.160 322.320 ;
      RECT 393.840 4.080 395.040 322.320 ;
      RECT 404.720 4.080 405.920 322.320 ;
      RECT 415.600 4.080 416.800 322.320 ;
      RECT 426.480 4.080 427.680 322.320 ;
      RECT 437.360 4.080 438.560 322.320 ;
      RECT 448.240 4.080 449.440 322.320 ;
      RECT 459.120 4.080 460.320 322.320 ;
      RECT 470.000 4.080 471.200 322.320 ;
      RECT 480.880 4.080 482.080 322.320 ;
      RECT 491.760 4.080 492.960 322.320 ;
      RECT 502.640 4.080 503.840 322.320 ;
      RECT 513.520 4.080 514.720 322.320 ;
      RECT 524.400 4.080 525.600 322.320 ;
      RECT 535.280 4.080 536.480 322.320 ;
      RECT 546.160 4.080 547.360 322.320 ;
      RECT 557.040 4.080 558.240 322.320 ;
      RECT 567.920 4.080 569.120 322.320 ;
      RECT 578.800 4.080 580.000 322.320 ;
      RECT 589.680 4.080 590.880 322.320 ;
      RECT 600.560 4.080 601.760 322.320 ;
      RECT 611.440 4.080 612.640 322.320 ;
      RECT 622.320 4.080 623.520 322.320 ;
      RECT 633.200 4.080 634.400 322.320 ;
      RECT 644.080 4.080 645.280 322.320 ;
      RECT 654.960 4.080 656.160 322.320 ;
      RECT 665.840 4.080 667.040 322.320 ;
      RECT 676.720 4.080 677.920 322.320 ;
      RECT 687.600 4.080 688.800 322.320 ;
      RECT 698.480 4.080 699.680 322.320 ;
      RECT 709.360 4.080 710.560 322.320 ;
      RECT 720.240 4.080 721.440 322.320 ;
      RECT 731.120 4.080 732.320 322.320 ;
      RECT 742.000 4.080 743.200 322.320 ;
      RECT 752.880 4.080 754.080 322.320 ;
      RECT 763.760 4.080 764.960 322.320 ;
      RECT 774.640 4.080 775.840 322.320 ;
      RECT 785.520 4.080 786.720 322.320 ;
      RECT 796.400 4.080 797.600 322.320 ;
      RECT 807.280 4.080 808.480 322.320 ;
      RECT 818.160 4.080 819.360 322.320 ;
      RECT 829.040 4.080 830.240 322.320 ;
      RECT 839.920 4.080 841.120 322.320 ;
      RECT 850.800 4.080 852.000 322.320 ;
      RECT 861.680 4.080 862.880 322.320 ;
      RECT 872.560 4.080 873.760 322.320 ;
      RECT 883.440 4.080 884.640 322.320 ;
      RECT 894.320 4.080 895.520 322.320 ;
      RECT 905.200 4.080 906.400 322.320 ;
      RECT 916.080 4.080 917.280 322.320 ;
      RECT 926.960 4.080 928.160 322.320 ;
      RECT 937.840 4.080 939.040 322.320 ;
      RECT 948.720 4.080 949.920 322.320 ;
      RECT 959.600 4.080 960.800 322.320 ;
      RECT 970.480 4.080 971.680 322.320 ;
      RECT 981.360 4.080 982.560 322.320 ;
      RECT 992.240 4.080 993.440 322.320 ;
      RECT 1003.120 4.080 1004.320 322.320 ;
      RECT 1014.000 4.080 1015.200 322.320 ;
      RECT 1024.880 4.080 1026.080 322.320 ;
      RECT 1035.760 4.080 1036.960 322.320 ;
      RECT 1046.640 4.080 1047.840 322.320 ;
      RECT 1057.520 4.080 1058.720 322.320 ;
      RECT 1068.400 4.080 1069.600 322.320 ;
      RECT 1079.280 4.080 1080.480 322.320 ;
      RECT 1090.160 4.080 1091.360 322.320 ;
      RECT 1101.040 4.080 1102.240 322.320 ;
      RECT 1111.920 4.080 1113.120 322.320 ;
      RECT 1122.800 4.080 1124.000 322.320 ;
      RECT 1133.680 4.080 1134.880 322.320 ;
      RECT 1144.560 4.080 1145.760 322.320 ;
      RECT 1155.440 4.080 1156.640 322.320 ;
      RECT 1166.320 4.080 1167.520 322.320 ;
      RECT 1177.200 4.080 1178.400 322.320 ;
      RECT 1188.080 4.080 1189.280 322.320 ;
      RECT 1198.960 4.080 1200.160 322.320 ;
      RECT 1209.840 4.080 1211.040 322.320 ;
      RECT 1220.720 4.080 1221.920 322.320 ;
      RECT 1231.600 4.080 1232.800 322.320 ;
      RECT 1242.480 4.080 1243.680 322.320 ;
      RECT 1253.360 4.080 1254.560 322.320 ;
      RECT 1264.240 4.080 1265.440 322.320 ;
      RECT 1275.120 4.080 1276.320 322.320 ;
      RECT 1286.000 4.080 1287.200 322.320 ;
      RECT 1296.880 4.080 1298.080 322.320 ;
      RECT 1307.760 4.080 1308.960 322.320 ;
      RECT 1318.640 4.080 1319.840 322.320 ;
      RECT 1329.520 4.080 1330.720 322.320 ;
      RECT 1340.400 4.080 1341.600 322.320 ;
      RECT 1351.280 4.080 1352.480 322.320 ;
    END
  END VDD
  OBS
    LAYER met1 ;
    RECT 0 0 1359.300 326.400 ;
    LAYER met2 ;
    RECT 0 0 1359.300 326.400 ;
    LAYER met3 ;
    RECT 0 0 1359.300 326.400 ;
    LAYER met4 ;
    RECT 0 0 1359.300 326.400 ;
  END
END fakeram130_1rw1r_92w256d

END LIBRARY
